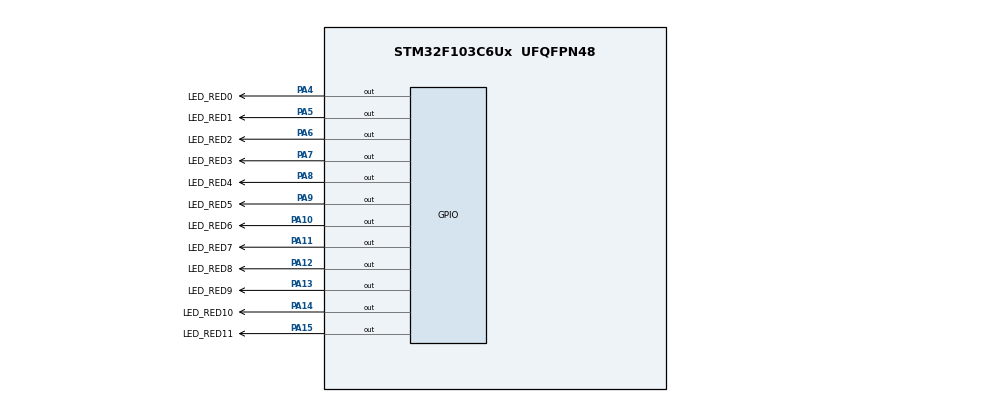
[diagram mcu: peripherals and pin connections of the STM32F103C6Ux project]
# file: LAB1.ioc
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Mcu.Family=STM32F1
Mcu.Name=STM32F103C6Ux
Mcu.Package=UFQFPN48
NVIC.PriorityGroup=NVIC_PRIORITYGROUP_4
PA10.GPIO_Label=LED_RED6
PA10.Signal=GPIO_Output
PA11.GPIO_Label=LED_RED7
PA11.Signal=GPIO_Output
PA12.GPIO_Label=LED_RED8
PA12.Signal=GPIO_Output
PA13.GPIO_Label=LED_RED9
PA13.Signal=GPIO_Output
PA14.GPIO_Label=LED_RED10
PA14.Signal=GPIO_Output
PA15.GPIO_Label=LED_RED11
PA15.Signal=GPIO_Output
PA4.GPIO_Label=LED_RED0
PA4.Signal=GPIO_Output
PA5.GPIO_Label=LED_RED1
PA5.Signal=GPIO_Output
PA6.GPIO_Label=LED_RED2
PA6.Signal=GPIO_Output
PA7.GPIO_Label=LED_RED3
PA7.Signal=GPIO_Output
PA8.GPIO_Label=LED_RED4
PA8.Signal=GPIO_Output
PA9.GPIO_Label=LED_RED5
PA9.Signal=GPIO_Output
ProjectManager.HeapSize=0x200
ProjectManager.StackSize=0x400
ProjectManager.TargetToolchain=STM32CubeIDE
RCC.APB1Freq_Value=8000000
RCC.APB2Freq_Value=8000000
VP_SYS_VS_ND.Mode=No_Debug
board=custom

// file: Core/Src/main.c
/* USER CODE BEGIN Header */
/**
  ******************************************************************************
  * @file           : main.c
  * @brief          : Main program body
  ******************************************************************************
  * @attention
  *
  * <h2><center>&copy; Copyright (c) 2023 STMicroelectronics.
  * All rights reserved.</center></h2>
  *
  * This software component is licensed by ST under BSD 3-Clause license,
  * the "License"; You may not use this file except in compliance with the
  * License. You may obtain a copy of the License at:
  *                        opensource.org/licenses/BSD-3-Clause
  *
  ******************************************************************************
  */
/* USER CODE END Header */
#include "main.h"
#include "softwaretimer.h"

void SystemClock_Config(void);
static void MX_GPIO_Init(void);

void display7SEG1(int num) {
	if(num==0) {
		HAL_GPIO_WritePin(a_GPIO_Port, a_Pin, RESET);
		HAL_GPIO_WritePin(b_GPIO_Port, b_Pin, RESET);
		HAL_GPIO_WritePin(c_GPIO_Port, c_Pin, RESET);
		HAL_GPIO_WritePin(d_GPIO_Port, d_Pin, RESET);
		HAL_GPIO_WritePin(e_GPIO_Port, e_Pin, RESET);
		HAL_GPIO_WritePin(f_GPIO_Port, f_Pin, RESET);
		HAL_GPIO_WritePin(g_GPIO_Port, g_Pin, SET);
	}
	else if(num==1) {
		HAL_GPIO_WritePin(a_GPIO_Port, a_Pin, SET);
		HAL_GPIO_WritePin(b_GPIO_Port, b_Pin, RESET);
		HAL_GPIO_WritePin(c_GPIO_Port, c_Pin, RESET);
		HAL_GPIO_WritePin(d_GPIO_Port, d_Pin, SET);
		HAL_GPIO_WritePin(e_GPIO_Port, e_Pin, SET);
		HAL_GPIO_WritePin(f_GPIO_Port, f_Pin, SET);
		HAL_GPIO_WritePin(g_GPIO_Port, g_Pin, SET);
	}
	else if(num==2) {
		HAL_GPIO_WritePin(a_GPIO_Port, a_Pin, RESET);
		HAL_GPIO_WritePin(b_GPIO_Port, b_Pin, RESET);
		HAL_GPIO_WritePin(c_GPIO_Port, c_Pin, SET);
		HAL_GPIO_WritePin(d_GPIO_Port, d_Pin, RESET);
		HAL_GPIO_WritePin(e_GPIO_Port, e_Pin, RESET);
		HAL_GPIO_WritePin(f_GPIO_Port, f_Pin, SET);
		HAL_GPIO_WritePin(g_GPIO_Port, g_Pin, RESET);
	}
	else if(num==3) {
		HAL_GPIO_WritePin(a_GPIO_Port, a_Pin, RESET);
		HAL_GPIO_WritePin(b_GPIO_Port, b_Pin, RESET);
		HAL_GPIO_WritePin(c_GPIO_Port, c_Pin, RESET);
		HAL_GPIO_WritePin(d_GPIO_Port, d_Pin, RESET);
		HAL_GPIO_WritePin(e_GPIO_Port, e_Pin, SET);
		HAL_GPIO_WritePin(f_GPIO_Port, f_Pin, SET);
		HAL_GPIO_WritePin(g_GPIO_Port, g_Pin, RESET);
	}
	else if(num==4) {
		HAL_GPIO_WritePin(a_GPIO_Port, a_Pin, SET);
		HAL_GPIO_WritePin(b_GPIO_Port, b_Pin, RESET);
		HAL_GPIO_WritePin(c_GPIO_Port, c_Pin, RESET);
		HAL_GPIO_WritePin(d_GPIO_Port, d_Pin, SET);
		HAL_GPIO_WritePin(e_GPIO_Port, e_Pin, SET);
		HAL_GPIO_WritePin(f_GPIO_Port, f_Pin, RESET);
		HAL_GPIO_WritePin(g_GPIO_Port, g_Pin, RESET);
	}
	else if(num==5) {
		HAL_GPIO_WritePin(a_GPIO_Port, a_Pin, RESET);
		HAL_GPIO_WritePin(b_GPIO_Port, b_Pin, SET);
		HAL_GPIO_WritePin(c_GPIO_Port, c_Pin, RESET);
		HAL_GPIO_WritePin(d_GPIO_Port, d_Pin, RESET);
		HAL_GPIO_WritePin(e_GPIO_Port, e_Pin, SET);
		HAL_GPIO_WritePin(f_GPIO_Port, f_Pin, RESET);
		HAL_GPIO_WritePin(g_GPIO_Port, g_Pin, RESET);
	}
	else if(num==6) {
		HAL_GPIO_WritePin(a_GPIO_Port, a_Pin, RESET);
		HAL_GPIO_WritePin(b_GPIO_Port, b_Pin, SET);
		HAL_GPIO_WritePin(c_GPIO_Port, c_Pin, RESET);
		HAL_GPIO_WritePin(d_GPIO_Port, d_Pin, RESET);
		HAL_GPIO_WritePin(e_GPIO_Port, e_Pin, RESET);
		HAL_GPIO_WritePin(f_GPIO_Port, f_Pin, RESET);
		HAL_GPIO_WritePin(g_GPIO_Port, g_Pin, RESET);
	}
	else if(num==7) {
		HAL_GPIO_WritePin(a_GPIO_Port, a_Pin, RESET);
		HAL_GPIO_WritePin(b_GPIO_Port, b_Pin, RESET);
		HAL_GPIO_WritePin(c_GPIO_Port, c_Pin, RESET);
		HAL_GPIO_WritePin(d_GPIO_Port, d_Pin, SET);
		HAL_GPIO_WritePin(e_GPIO_Port, e_Pin, SET);
		HAL_GPIO_WritePin(f_GPIO_Port, f_Pin, SET);
		HAL_GPIO_WritePin(g_GPIO_Port, g_Pin, SET);
	}
	else if(num==8) {
		HAL_GPIO_WritePin(a_GPIO_Port, a_Pin, RESET);
		HAL_GPIO_WritePin(b_GPIO_Port, b_Pin, RESET);
		HAL_GPIO_WritePin(c_GPIO_Port, c_Pin, RESET);
		HAL_GPIO_WritePin(d_GPIO_Port, d_Pin, RESET);
		HAL_GPIO_WritePin(e_GPIO_Port, e_Pin, RESET);
		HAL_GPIO_WritePin(f_GPIO_Port, f_Pin, RESET);
		HAL_GPIO_WritePin(g_GPIO_Port, g_Pin, RESET);
	}
	else if(num==9) {
		HAL_GPIO_WritePin(a_GPIO_Port, a_Pin, RESET);
		HAL_GPIO_WritePin(b_GPIO_Port, b_Pin, RESET);
		HAL_GPIO_WritePin(c_GPIO_Port, c_Pin, RESET);
		HAL_GPIO_WritePin(d_GPIO_Port, d_Pin, RESET);
		HAL_GPIO_WritePin(e_GPIO_Port, e_Pin, SET);
		HAL_GPIO_WritePin(f_GPIO_Port, f_Pin, RESET);
		HAL_GPIO_WritePin(g_GPIO_Port, g_Pin, RESET);
	}
}
void display7SEG2(int num) {
	if(num==0) {
		HAL_GPIO_WritePin(a2_GPIO_Port, a2_Pin, RESET);
		HAL_GPIO_WritePin(b2_GPIO_Port, b2_Pin, RESET);
		HAL_GPIO_WritePin(c2_GPIO_Port, c2_Pin, RESET);
		HAL_GPIO_WritePin(d2_GPIO_Port, d2_Pin, RESET);
		HAL_GPIO_WritePin(e2_GPIO_Port, e2_Pin, RESET);
		HAL_GPIO_WritePin(f2_GPIO_Port, f2_Pin, RESET);
		HAL_GPIO_WritePin(g2_GPIO_Port, g2_Pin, SET);
	}
	else if(num==1) {
		HAL_GPIO_WritePin(a2_GPIO_Port, a2_Pin, SET);
		HAL_GPIO_WritePin(b2_GPIO_Port, b2_Pin, RESET);
		HAL_GPIO_WritePin(c2_GPIO_Port, c2_Pin, RESET);
		HAL_GPIO_WritePin(d2_GPIO_Port, d2_Pin, SET);
		HAL_GPIO_WritePin(e2_GPIO_Port, e2_Pin, SET);
		HAL_GPIO_WritePin(f2_GPIO_Port, f2_Pin, SET);
		HAL_GPIO_WritePin(g2_GPIO_Port, g2_Pin, SET);
	}
	else if(num==2) {
		HAL_GPIO_WritePin(a2_GPIO_Port, a2_Pin, RESET);
		HAL_GPIO_WritePin(b2_GPIO_Port, b2_Pin, RESET);
		HAL_GPIO_WritePin(c2_GPIO_Port, c2_Pin, SET);
		HAL_GPIO_WritePin(d2_GPIO_Port, d2_Pin, RESET);
		HAL_GPIO_WritePin(e2_GPIO_Port, e2_Pin, RESET);
		HAL_GPIO_WritePin(f2_GPIO_Port, f2_Pin, SET);
		HAL_GPIO_WritePin(g2_GPIO_Port, g2_Pin, RESET);
	}
	else if(num==3) {
		HAL_GPIO_WritePin(a2_GPIO_Port, a2_Pin, RESET);
		HAL_GPIO_WritePin(b2_GPIO_Port, b2_Pin, RESET);
		HAL_GPIO_WritePin(c2_GPIO_Port, c2_Pin, RESET);
		HAL_GPIO_WritePin(d2_GPIO_Port, d2_Pin, RESET);
		HAL_GPIO_WritePin(e2_GPIO_Port, e2_Pin, SET);
		HAL_GPIO_WritePin(f2_GPIO_Port, f2_Pin, SET);
		HAL_GPIO_WritePin(g2_GPIO_Port, g2_Pin, RESET);
	}
	else if(num==4) {
		HAL_GPIO_WritePin(a2_GPIO_Port, a2_Pin, SET);
		HAL_GPIO_WritePin(b2_GPIO_Port, b2_Pin, RESET);
		HAL_GPIO_WritePin(c2_GPIO_Port, c2_Pin, RESET);
		HAL_GPIO_WritePin(d2_GPIO_Port, d2_Pin, SET);
		HAL_GPIO_WritePin(e2_GPIO_Port, e2_Pin, SET);
		HAL_GPIO_WritePin(f2_GPIO_Port, f2_Pin, RESET);
		HAL_GPIO_WritePin(g2_GPIO_Port, g2_Pin, RESET);
	}
	else if(num==5) {
		HAL_GPIO_WritePin(a2_GPIO_Port, a2_Pin, RESET);
		HAL_GPIO_WritePin(b2_GPIO_Port, b2_Pin, SET);
		HAL_GPIO_WritePin(c2_GPIO_Port, c2_Pin, RESET);
		HAL_GPIO_WritePin(d2_GPIO_Port, d2_Pin, RESET);
		HAL_GPIO_WritePin(e2_GPIO_Port, e2_Pin, SET);
		HAL_GPIO_WritePin(f2_GPIO_Port, f2_Pin, RESET);
		HAL_GPIO_WritePin(g2_GPIO_Port, g2_Pin, RESET);
	}
	else if(num==6) {
		HAL_GPIO_WritePin(a2_GPIO_Port, a2_Pin, RESET);
		HAL_GPIO_WritePin(b2_GPIO_Port, b2_Pin, SET);
		HAL_GPIO_WritePin(c2_GPIO_Port, c2_Pin, RESET);
		HAL_GPIO_WritePin(d2_GPIO_Port, d2_Pin, RESET);
		HAL_GPIO_WritePin(e2_GPIO_Port, e2_Pin, RESET);
		HAL_GPIO_WritePin(f2_GPIO_Port, f2_Pin, RESET);
		HAL_GPIO_WritePin(g2_GPIO_Port, g2_Pin, RESET);
	}
	else if(num==7) {
		HAL_GPIO_WritePin(a2_GPIO_Port, a2_Pin, RESET);
		HAL_GPIO_WritePin(b2_GPIO_Port, b2_Pin, RESET);
		HAL_GPIO_WritePin(c2_GPIO_Port, c2_Pin, RESET);
		HAL_GPIO_WritePin(d2_GPIO_Port, d2_Pin, SET);
		HAL_GPIO_WritePin(e2_GPIO_Port, e2_Pin, SET);
		HAL_GPIO_WritePin(f2_GPIO_Port, f2_Pin, SET);
		HAL_GPIO_WritePin(g2_GPIO_Port, g2_Pin, SET);
	}
	else if(num==8) {
		HAL_GPIO_WritePin(a2_GPIO_Port, a2_Pin, RESET);
		HAL_GPIO_WritePin(b2_GPIO_Port, b2_Pin, RESET);
		HAL_GPIO_WritePin(c2_GPIO_Port, c2_Pin, RESET);
		HAL_GPIO_WritePin(d2_GPIO_Port, d2_Pin, RESET);
		HAL_GPIO_WritePin(e2_GPIO_Port, e2_Pin, RESET);
		HAL_GPIO_WritePin(f2_GPIO_Port, f2_Pin, RESET);
		HAL_GPIO_WritePin(g2_GPIO_Port, g2_Pin, RESET);
	}
	else if(num==9) {
		HAL_GPIO_WritePin(a2_GPIO_Port, a2_Pin, RESET);
		HAL_GPIO_WritePin(b2_GPIO_Port, b2_Pin, RESET);
		HAL_GPIO_WritePin(c2_GPIO_Port, c2_Pin, RESET);
		HAL_GPIO_WritePin(d2_GPIO_Port, d2_Pin, RESET);
		HAL_GPIO_WritePin(e2_GPIO_Port, e2_Pin, SET);
		HAL_GPIO_WritePin(f2_GPIO_Port, f2_Pin, RESET);
		HAL_GPIO_WritePin(g2_GPIO_Port, g2_Pin, RESET);
	}
}
int main(void)
{

  /* MCU Configuration--------------------------------------------------------*/

  /* Reset of all peripherals, Initializes the Flash interface and the Systick. */
  HAL_Init();

  /* Configure the system clock */
  SystemClock_Config();

  /* Initialize all configured peripherals */
  MX_GPIO_Init();

  /* Infinite loop */
  setTimer1(300);
  /* USER CODE BEGIN WHILE */
  //state 1: (1) red 3s; (2) green 3s
  //state 2: (1) red 2s; (2) yellow 2s
  //state 3: (1) green 3s; (2) red 3s
  //state 4: (1) yellow 2s; (2) red 2s
  enum State{state1, state2, state3, state4};
  enum State currentState=state1;
  enum State nextState=currentState;
  while (1)
  {
	  //ex5
	  switch (currentState) {
	  case state1:
		  HAL_GPIO_WritePin(LED_RED1_GPIO_Port, LED_RED1_Pin, RESET);
		  HAL_GPIO_WritePin(LED_YELLOW1_GPIO_Port, LED_YELLOW1_Pin, SET);
		  HAL_GPIO_WritePin(LED_GREEN1_GPIO_Port, LED_GREEN1_Pin, SET);

		  HAL_GPIO_WritePin(LED_RED2_GPIO_Port, LED_RED2_Pin, SET);
		  HAL_GPIO_WritePin(LED_YELLOW2_GPIO_Port, LED_YELLOW2_Pin, SET);
		  HAL_GPIO_WritePin(LED_GREEN2_GPIO_Port, LED_GREEN2_Pin, RESET);

		  if (timer1_counter%100==0){ //timer1_counter=300;200;100
			  //int n=timer1_counter/100;
			  display7SEG1(timer1_counter/100 +2); //red in 1st group count from 5
			  display7SEG2(timer1_counter/100); //green in 2nd group
		  }
		  if(timer1_flag ==1) {
			  nextState=state2;
			  setTimer2(200);
		  }
		  break;
	  case state2:
		  HAL_GPIO_WritePin(LED_RED1_GPIO_Port, LED_RED1_Pin, RESET);
		  HAL_GPIO_WritePin(LED_YELLOW1_GPIO_Port, LED_YELLOW1_Pin, SET);
		  HAL_GPIO_WritePin(LED_GREEN1_GPIO_Port, LED_GREEN1_Pin, SET);

		  HAL_GPIO_WritePin(LED_RED2_GPIO_Port, LED_RED2_Pin, SET);
		  HAL_GPIO_WritePin(LED_YELLOW2_GPIO_Port, LED_YELLOW2_Pin, RESET);
		  HAL_GPIO_WritePin(LED_GREEN2_GPIO_Port, LED_GREEN2_Pin, SET);

		  if (timer2_counter%100==0){ //timer2_counter=200;100
			  //int n=timer2_counter/100;
			  display7SEG1(timer2_counter/100); //red in 1st group continues from 2
			  display7SEG2(timer2_counter/100); //yellow in 2nd group
		  }
		  if(timer2_flag ==1) {
			  nextState=state3;
			  setTimer3(300);
		  }
		  break;
	  case state3:
		  HAL_GPIO_WritePin(LED_RED1_GPIO_Port, LED_RED1_Pin, SET);
		  HAL_GPIO_WritePin(LED_YELLOW1_GPIO_Port, LED_YELLOW1_Pin, SET);
		  HAL_GPIO_WritePin(LED_GREEN1_GPIO_Port, LED_GREEN1_Pin, RESET);

		  HAL_GPIO_WritePin(LED_RED2_GPIO_Port, LED_RED2_Pin, RESET);
		  HAL_GPIO_WritePin(LED_YELLOW2_GPIO_Port, LED_YELLOW2_Pin, SET);
		  HAL_GPIO_WritePin(LED_GREEN2_GPIO_Port, LED_GREEN2_Pin, SET);

		  if (timer3_counter%100==0){ //timer3_counter=300;200;100
			  //int n=timer3_counter/100;
			  display7SEG1(timer3_counter/100); //green in 1st group
			  display7SEG2(timer3_counter/100 +2); //red in 2nd group
		  }
		  if(timer3_flag ==1) {
			  nextState=state4;
			  setTimer4(200);
		  }
		  break;

	 case state4:
		  HAL_GPIO_WritePin(LED_RED1_GPIO_Port, LED_RED1_Pin, SET);
		  HAL_GPIO_WritePin(LED_YELLOW1_GPIO_Port, LED_YELLOW1_Pin, RESET);
		  HAL_GPIO_WritePin(LED_GREEN1_GPIO_Port, LED_GREEN1_Pin, SET);

		  HAL_GPIO_WritePin(LED_RED2_GPIO_Port, LED_RED2_Pin, RESET);
		  HAL_GPIO_WritePin(LED_YELLOW2_GPIO_Port, LED_YELLOW2_Pin, SET);
		  HAL_GPIO_WritePin(LED_GREEN2_GPIO_Port, LED_GREEN2_Pin, SET);

		  if (timer4_counter%100==0){ //timer4_counter=200;100
			  //int n=timer4_counter/100;
			  display7SEG1(timer4_counter/100); //yellow in 1st group
			  display7SEG2(timer4_counter/100); //red continues from 2 in 2nd group
		  }
		  if(timer4_flag ==1) {
			  nextState=state1;
			  setTimer1(301);
		  }
		  break;
	  }
	  timerRun();
	  currentState=nextState;
	  HAL_Delay(10);

    /* USER CODE END WHILE */

  }
}

void SystemClock_Config(void)
{
  RCC_OscInitTypeDef RCC_OscInitStruct = {0};
  RCC_ClkInitTypeDef RCC_ClkInitStruct = {0};

  /** Initializes the RCC Oscillators according to the specified parameters
  * in the RCC_OscInitTypeDef structure.
  */
  RCC_OscInitStruct.OscillatorType = RCC_OSCILLATORTYPE_HSI;
  RCC_OscInitStruct.HSIState = RCC_HSI_ON;
  RCC_OscInitStruct.HSICalibrationValue = RCC_HSICALIBRATION_DEFAULT;
  RCC_OscInitStruct.PLL.PLLState = RCC_PLL_NONE;
  if (HAL_RCC_OscConfig(&RCC_OscInitStruct) != HAL_OK)
  {
    Error_Handler();
  }
  /** Initializes the CPU, AHB and APB buses clocks
  */
  RCC_ClkInitStruct.ClockType = RCC_CLOCKTYPE_HCLK|RCC_CLOCKTYPE_SYSCLK
                              |RCC_CLOCKTYPE_PCLK1|RCC_CLOCKTYPE_PCLK2;
  RCC_ClkInitStruct.SYSCLKSource = RCC_SYSCLKSOURCE_HSI;
  RCC_ClkInitStruct.AHBCLKDivider = RCC_SYSCLK_DIV1;
  RCC_ClkInitStruct.APB1CLKDivider = RCC_HCLK_DIV1;
  RCC_ClkInitStruct.APB2CLKDivider = RCC_HCLK_DIV1;

  if (HAL_RCC_ClockConfig(&RCC_ClkInitStruct, FLASH_LATENCY_0) != HAL_OK)
  {
    Error_Handler();
  }
}

static void MX_GPIO_Init(void)
{
  GPIO_InitTypeDef GPIO_InitStruct = {0};

  /* GPIO Ports Clock Enable */
  __HAL_RCC_GPIOA_CLK_ENABLE();
  __HAL_RCC_GPIOB_CLK_ENABLE();

  /*Configure GPIO pin Output Level */
  HAL_GPIO_WritePin(GPIOA, LED_RED1_Pin|LED_YELLOW1_Pin|LED_GREEN1_Pin|LED_RED2_Pin
                          |LED_YELLOW2_Pin|LED_GREEN2_Pin, GPIO_PIN_RESET);

  /*Configure GPIO pin Output Level */
  HAL_GPIO_WritePin(GPIOB, a_Pin|b_Pin|c_Pin|d2_Pin
                          |e2_Pin|f2_Pin|g2_Pin|d_Pin
                          |e_Pin|f_Pin|g_Pin|a2_Pin
                          |b2_Pin|c2_Pin, GPIO_PIN_RESET);

  /*Configure GPIO pins : LED_RED1_Pin LED_YELLOW1_Pin LED_GREEN1_Pin LED_RED2_Pin
                           LED_YELLOW2_Pin LED_GREEN2_Pin */
  GPIO_InitStruct.Pin = LED_RED1_Pin|LED_YELLOW1_Pin|LED_GREEN1_Pin|LED_RED2_Pin
                          |LED_YELLOW2_Pin|LED_GREEN2_Pin;
  GPIO_InitStruct.Mode = GPIO_MODE_OUTPUT_PP;
  GPIO_InitStruct.Pull = GPIO_NOPULL;
  GPIO_InitStruct.Speed = GPIO_SPEED_FREQ_LOW;
  HAL_GPIO_Init(GPIOA, &GPIO_InitStruct);

  /*Configure GPIO pins : a_Pin b_Pin c_Pin d2_Pin
                           e2_Pin f2_Pin g2_Pin d_Pin
                           e_Pin f_Pin g_Pin a2_Pin
                           b2_Pin c2_Pin */
  GPIO_InitStruct.Pin = a_Pin|b_Pin|c_Pin|d2_Pin
                          |e2_Pin|f2_Pin|g2_Pin|d_Pin
                          |e_Pin|f_Pin|g_Pin|a2_Pin
                          |b2_Pin|c2_Pin;
  GPIO_InitStruct.Mode = GPIO_MODE_OUTPUT_PP;
  GPIO_InitStruct.Pull = GPIO_NOPULL;
  GPIO_InitStruct.Speed = GPIO_SPEED_FREQ_LOW;
  HAL_GPIO_Init(GPIOB, &GPIO_InitStruct);

}

void Error_Handler(void)
{
  __disable_irq();
  while (1)
  {
  }
}

/************************ (C) COPYRIGHT STMicroelectronics *****END OF FILE****/
